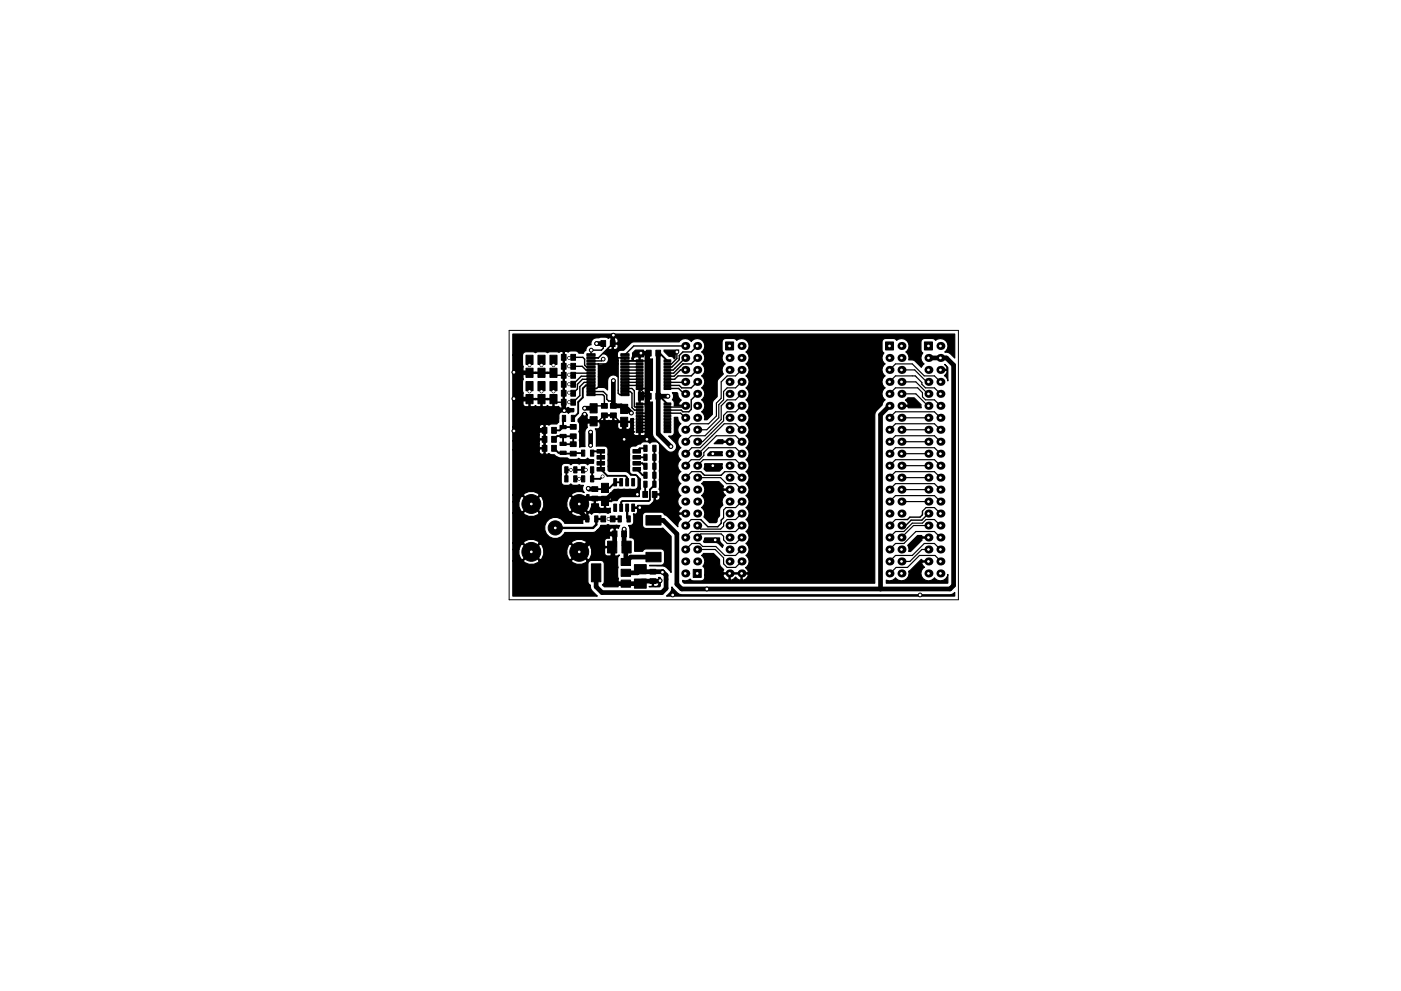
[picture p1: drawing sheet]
<svg xmlns="http://www.w3.org/2000/svg" width="297mm" height="210mm" viewBox="0 0 297 210" stroke-linecap="round" stroke-linejoin="round" font-family="sans-serif">
<path d="M107.9 70.1h95.3v57.1h-95.3z" fill="none" stroke="#000" stroke-width=".21"/>
<g fill="#000" stroke="#000" stroke-width=".21">
<path d="M111.5 75.4h1.5v1.9h-1.5zM111.5 78.1h1.5v2h-1.5zM114.1 75.4h1.5v1.9h-1.5zM114.1 78.1h1.5v2h-1.5zM116.6 75.4h1.5v1.9h-1.5zM116.6 78.1h1.5v2h-1.5zM119 79h1v1.2h-1zM119 77.1h1v1.2h-1zM119 75.2h1v1.2h-1zM121 79h1v1.2h-1zM121 77.1h1v1.2h-1zM121 75.2h1v1.2h-1z"/>
<path d="M124.4 75h1.8v.5h-1.8zM124.4 75.7h1.8v.4h-1.8zM124.4 76.3h1.8v.5h-1.8zM124.4 77h1.8v.4h-1.8zM124.4 77.6h1.8v.5h-1.8zM124.4 78.3h1.8v.4h-1.8zM124.4 78.9h1.8v.5h-1.8zM124.4 79.6h1.8v.4h-1.8zM127.4 72.3h1v1.2h-1zM129.4 72.3h1v1.2h-1zM131.6 79.6h1.8v.4h-1.8zM131.6 78.9h1.8v.5h-1.8z"/>
<path d="M131.6 78.3h1.8v.4h-1.8zM131.6 77.6h1.8v.5h-1.8zM131.6 77h1.8v.4h-1.8zM131.6 76.3h1.8v.5h-1.8zM131.6 75.7h1.8v.4h-1.8zM131.6 75h1.8v.5h-1.8zM134.9 76.3h1.4v.5h-1.4zM134.9 77h1.4v.4h-1.4zM134.9 77.6h1.4v.5h-1.4zM134.9 78.3h1.4v.4h-1.4zM134.9 78.9h1.4v.5h-1.4zM137.1 74.3h1v1.2h-1z"/>
<path d="M139.1 74.3h1v1.2h-1zM140.8 78.9h1.4v.5h-1.4zM140.8 78.3h1.4v.4h-1.4zM140.8 77.6h1.4v.5h-1.4zM140.8 77h1.4v.4h-1.4zM140.8 76.3h1.4v.5h-1.4zM153.8 72.6h1.7v1.7h-1.7zM187.7 72.6h1.7v1.7h-1.7zM196 72.6h1.7v1.7h-1.7zM111.5 81h1.5v1.9h-1.5zM111.5 83.7h1.5v2h-1.5zM114.1 81h1.5v1.9h-1.5z"/>
<path d="M114.1 83.7h1.5v2h-1.5zM115 94.5h1v1.2h-1zM115 92.6h1v1.2h-1zM115 90.7h1v1.2h-1zM116.6 81h1.5v1.9h-1.5zM116.6 83.7h1.5v2h-1.5zM117 94.5h1v1.2h-1zM117 92.6h1v1.2h-1zM117 90.7h1v1.2h-1zM118.7 93.8h1.3v.7h-1.3zM118.7 95.7h1.3v.7h-1.3zM118.7 90.3h1.3v.7h-1.3z"/>
<path d="M118.7 92.2h1.3v.7h-1.3zM119.2 88.1h.7v1.3h-.7zM119 84.7h1v1.3h-1zM119 80.9h1v1.3h-1zM119 82.8h1v1.3h-1zM119.7 99h.7v1.3h-.7zM121.1 88.1h.7v1.3h-.7zM121 84.7h1v1.3h-1zM121 80.9h1v1.3h-1zM121 82.8h1v1.3h-1zM120.9 95.7h1.3v1h-1.3zM120.9 93.7h1.3v1h-1.3z"/>
<path d="M120.9 92.1h1.3v1h-1.3zM120.9 90.1h1.3v1h-1.3zM121.6 99h.7v1.3h-.7zM123.3 95.5h.7v1.3h-.7zM125.1 85.7h1.5v1.9h-1.5zM125.1 88.4h1.5v2h-1.5zM125.2 95.5h.7v1.3h-.7zM124.4 80.2h1.8v.5h-1.8zM124.4 80.9h1.8v.4h-1.8zM124.4 81.5h1.8v.5h-1.8zM124.4 82.2h1.8v.4h-1.8zM124.4 82.8h1.8v.5h-1.8z"/>
<path d="M124.4 83.5h1.8v.4h-1.8zM127.5 85.6h1.3v1h-1.3zM127.5 87.6h1.3v1h-1.3zM126.6 95.4h1.6v.7h-1.6zM126.6 96.6h1.6v.8h-1.6zM126.6 97.9h1.6v.8h-1.6zM126.6 99.2h1.6v.7h-1.6zM129.4 85.6h1.3v1h-1.3zM129.4 87.6h1.3v1h-1.3zM131.6 85.8h1.5v1.9h-1.5zM131.6 88.5h1.5v2h-1.5zM131.6 83.5h1.8v.4h-1.8z"/>
<path d="M131.6 82.8h1.8v.5h-1.8zM131.6 82.2h1.8v.4h-1.8zM131.6 81.5h1.8v.5h-1.8zM131.6 80.9h1.8v.4h-1.8zM131.6 80.2h1.8v.5h-1.8zM134.9 79.6h1.4v.4h-1.4zM134.9 80.2h1.4v.5h-1.4zM134.9 80.9h1.4v.4h-1.4zM134.9 81.5h1.4v.5h-1.4zM134.9 82.2h1.4v.4h-1.4zM134.9 85.5h1.4v.4h-1.4zM134.9 86.1h1.4v.5h-1.4z"/>
<path d="M134.9 86.8h1.4v.4h-1.4zM134.9 87.4h1.4v.5h-1.4zM134.9 88.1h1.4v.4h-1.4zM134.9 88.7h1.4v.5h-1.4zM134.9 89.4h1.4v.4h-1.4zM134.9 90h1.4v.5h-1.4zM134.9 90.7h1.4v.4h-1.4zM134.9 91.3h1.4v.5h-1.4zM134.2 99.2h1.6v.7h-1.6zM134.2 97.9h1.6v.8h-1.6zM134.2 96.6h1.6v.8h-1.6zM134.2 95.4h1.6v.7h-1.6z"/>
<path d="M136.5 98.3h.7v1.3h-.7zM136.5 96.4h.7v1.3h-.7zM136.5 94.5h.7v1.3h-.7zM137.1 83.4h1v1.3h-1zM138.4 98.3h.7v1.3h-.7zM138.4 96.4h.7v1.3h-.7zM138.4 94.5h.7v1.3h-.7zM139.1 83.4h1v1.3h-1zM140.8 82.2h1.4v.4h-1.4zM140.8 81.5h1.4v.5h-1.4zM140.8 80.9h1.4v.4h-1.4zM140.8 80.2h1.4v.5h-1.4z"/>
<path d="M140.8 79.6h1.4v.4h-1.4zM140.8 91.3h1.4v.5h-1.4zM140.8 90.7h1.4v.4h-1.4zM140.8 90h1.4v.5h-1.4zM140.8 89.4h1.4v.4h-1.4zM140.8 88.7h1.4v.5h-1.4zM140.8 88.1h1.4v.4h-1.4zM140.8 87.4h1.4v.5h-1.4zM140.8 86.8h1.4v.4h-1.4zM140.8 86.1h1.4v.5h-1.4zM140.8 85.5h1.4v.4h-1.4zM119.7 100.9h.7v1.3h-.7z"/>
<path d="M121.6 100.9h.7v1.3h-.7zM123.3 99h.7v1.3h-.7zM123.3 100.9h.7v1.3h-.7zM124.2 109.5h.7v1.3h-.7zM125.2 99h.7v1.3h-.7zM125.5 103.3h1.2v1h-1.2zM125.5 105.3h1.2v1h-1.2zM125.2 100.9h.7v1.3h-.7zM126.1 109.5h.7v1.3h-.7zM125.4 119.6h2v3.8h-2zM127.5 102.5h1.5v2h-1.5zM127.5 105.3h1.5v1.9h-1.5z"/>
<path d="M127.4 109.5h1v1.2h-1zM129.4 109.5h1v1.2h-1zM130.1 106.9h.6v1.6h-.6zM130.1 101.5h.6v1.6h-.6zM128.8 114.8h2v2.5h-2zM129.8 112.7h1v1.2h-1zM131 109.5h.7v1.3h-.7zM131.4 106.9h.6v1.6h-.6zM131.4 101.5h.6v1.6h-.6zM131.8 112.7h1v1.2h-1zM132.9 109.5h.7v1.3h-.7zM132.7 106.9h.6v1.6h-.6z"/>
<path d="M132.7 101.5h.6v1.6h-.6zM131.7 118.5h2v1.5h-2zM131.9 114.8h1.9v2.5h-1.9zM134.5 119.8h2.5v1.9h-2.5zM133.9 106.9h.6v1.6h-.6zM133.9 101.5h.6v1.6h-.6zM136.3 104.3h1v1.2h-1zM136.5 102.1h.7v1.3h-.7zM136.5 100.2h.7v1.3h-.7zM138.3 104.3h1v1.2h-1zM138.4 102.1h.7v1.3h-.7zM138.4 100.2h.7v1.3h-.7z"/>
<path d="M137 117.2h3.2v2h-3.2zM137 109.4h3.2v2h-3.2zM131.7 120.8h2v1.5h-2zM131.7 123.1h2v1.5h-2zM134.5 122.8h2.5v2h-2.5zM137.8 120.8h1.3v1h-1.3zM137.8 122.8h1.3v1h-1.3zM147 120.8h1.7v1.7h-1.7z"/>
<circle cx="109" cy="79" r=".4"/>
<circle cx="112.3" cy="77.5" r=".3"/>
<circle cx="114.8" cy="77.5" r=".3"/>
<circle cx="117.3" cy="77.5" r=".3"/>
<circle cx="120.7" cy="79.5" r=".3"/>
<circle cx="120.7" cy="77.7" r=".3"/>
<circle cx="120.7" cy="75.9" r=".3"/>
<circle cx="125.3" cy="74.3" r=".4"/>
<circle cx="126.5" cy="72.9" r=".4"/>
<circle cx="127.9" cy="76.2" r=".4"/>
<circle cx="130" cy="71.1" r=".4"/>
<circle cx="135.9" cy="74.9" r=".4"/>
<circle cx="143.5" cy="74.7" r=".4"/>
<circle cx="109" cy="84.6" r=".4"/>
<circle cx="109" cy="91.4" r=".4"/>
<circle cx="112.3" cy="83.1" r=".3"/>
<circle cx="114.8" cy="83.1" r=".3"/>
<circle cx="117.3" cy="83.1" r=".3"/>
<circle cx="119.6" cy="87.1" r=".4"/>
<circle cx="120.7" cy="85.3" r=".3"/>
<circle cx="120.7" cy="81.5" r=".3"/>
<circle cx="120.7" cy="83.3" r=".3"/>
<circle cx="121" cy="99.7" r=".3"/>
<circle cx="124" cy="86.6" r=".4"/>
<circle cx="124" cy="87.9" r=".4"/>
<circle cx="124.2" cy="99.7" r=".3"/>
<circle cx="125.2" cy="94.5" r=".4"/>
<circle cx="125.2" cy="91.7" r=".4"/>
<circle cx="130" cy="80.8" r=".4"/>
<circle cx="132.3" cy="93.2" r=".4"/>
<circle cx="133.9" cy="87.6" r=".4"/>
<circle cx="137.2" cy="93.2" r=".4"/>
<circle cx="141.6" cy="84.1" r=".4"/>
<circle cx="142.2" cy="94.7" r=".4"/>
<circle cx="151.1" cy="96.3" r=".4"/>
<circle cx="151.1" cy="98.8" r=".4"/>
<circle cx="112.6" cy="106.9" r="2"/>
<circle cx="112.6" cy="117.1" r="2"/>
<circle cx="117.7" cy="112" r="1.5"/>
<circle cx="122.8" cy="106.9" r="2"/>
<circle cx="122.8" cy="117.1" r="2"/>
<circle cx="122.8" cy="101.6" r=".3"/>
<circle cx="124.7" cy="103.6" r=".4"/>
<circle cx="127.8" cy="101.1" r=".3"/>
<circle cx="129" cy="110.1" r=".3"/>
<circle cx="132.3" cy="112.3" r=".4"/>
<circle cx="135.1" cy="104.9" r=".4"/>
<circle cx="135.6" cy="107.7" r=".4"/>
<circle cx="151.6" cy="114.5" r=".4"/>
<circle cx="140" cy="123.2" r=".4"/>
<circle cx="140.5" cy="121.4" r=".4"/>
<circle cx="142.6" cy="126.2" r=".4"/>
<circle cx="149.9" cy="125" r=".4"/>
<circle cx="195.1" cy="126.2" r=".4"/>
</g>
<g fill="#000">
<circle cx="145.3" cy="78.5" r=".85"/>
<circle cx="145.3" cy="75.9" r=".85"/>
<circle cx="145.3" cy="73.4" r=".85"/>
<circle cx="147.8" cy="78.5" r=".85"/>
<circle cx="147.8" cy="73.4" r=".85"/>
<circle cx="147.8" cy="75.9" r=".85"/>
<circle cx="154.7" cy="78.5" r=".85"/>
<circle cx="154.7" cy="75.9" r=".85"/>
<circle cx="157.2" cy="78.5" r=".85"/>
<circle cx="157.2" cy="73.4" r=".85"/>
<circle cx="157.2" cy="75.9" r=".85"/>
<circle cx="188.6" cy="78.5" r=".85"/>
<circle cx="188.6" cy="75.9" r=".85"/>
<circle cx="191.1" cy="78.5" r=".85"/>
<circle cx="191.1" cy="73.4" r=".85"/>
<circle cx="191.1" cy="75.9" r=".85"/>
<circle cx="196.8" cy="78.5" r=".85"/>
<circle cx="196.8" cy="75.9" r=".85"/>
<circle cx="199.4" cy="73.4" r=".85"/>
<circle cx="199.4" cy="78.5" r=".85"/>
<circle cx="199.4" cy="75.9" r=".85"/>
<circle cx="145.3" cy="96.3" r=".85"/>
<circle cx="145.3" cy="88.6" r=".85"/>
<circle cx="145.3" cy="83.6" r=".85"/>
<circle cx="145.3" cy="81" r=".85"/>
<circle cx="145.3" cy="93.7" r=".85"/>
<circle cx="145.3" cy="86.1" r=".85"/>
<circle cx="145.3" cy="98.8" r=".85"/>
<circle cx="145.3" cy="91.2" r=".85"/>
<circle cx="147.8" cy="93.7" r=".85"/>
<circle cx="147.8" cy="88.6" r=".85"/>
<circle cx="147.8" cy="86.1" r=".85"/>
<circle cx="147.8" cy="96.3" r=".85"/>
<circle cx="147.8" cy="91.2" r=".85"/>
<circle cx="147.8" cy="81" r=".85"/>
<circle cx="147.8" cy="98.8" r=".85"/>
<circle cx="147.8" cy="83.6" r=".85"/>
<circle cx="154.7" cy="93.7" r=".85"/>
<circle cx="154.7" cy="96.3" r=".85"/>
<circle cx="154.7" cy="81" r=".85"/>
<circle cx="154.7" cy="86.1" r=".85"/>
<circle cx="154.7" cy="83.6" r=".85"/>
<circle cx="154.7" cy="91.2" r=".85"/>
<circle cx="154.7" cy="98.8" r=".85"/>
<circle cx="154.7" cy="88.6" r=".85"/>
<circle cx="157.2" cy="96.3" r=".85"/>
<circle cx="157.2" cy="93.7" r=".85"/>
<circle cx="157.2" cy="86.1" r=".85"/>
<circle cx="157.2" cy="81" r=".85"/>
<circle cx="157.2" cy="83.6" r=".85"/>
<circle cx="157.2" cy="88.6" r=".85"/>
<circle cx="157.2" cy="91.2" r=".85"/>
<circle cx="157.2" cy="98.8" r=".85"/>
<circle cx="188.6" cy="96.3" r=".85"/>
<circle cx="188.6" cy="88.6" r=".85"/>
<circle cx="188.6" cy="86.1" r=".85"/>
<circle cx="188.6" cy="93.7" r=".85"/>
<circle cx="188.6" cy="83.6" r=".85"/>
<circle cx="188.6" cy="91.2" r=".85"/>
<circle cx="188.6" cy="81" r=".85"/>
<circle cx="188.6" cy="98.8" r=".85"/>
<circle cx="191.1" cy="86.1" r=".85"/>
<circle cx="191.1" cy="83.6" r=".85"/>
<circle cx="191.1" cy="88.6" r=".85"/>
<circle cx="191.1" cy="91.2" r=".85"/>
<circle cx="191.1" cy="93.7" r=".85"/>
<circle cx="191.1" cy="96.3" r=".85"/>
<circle cx="191.1" cy="81" r=".85"/>
<circle cx="191.1" cy="98.8" r=".85"/>
<circle cx="196.8" cy="91.2" r=".85"/>
<circle cx="196.8" cy="86.1" r=".85"/>
<circle cx="196.8" cy="88.6" r=".85"/>
<circle cx="196.8" cy="93.7" r=".85"/>
<circle cx="196.8" cy="81" r=".85"/>
<circle cx="196.8" cy="83.6" r=".85"/>
<circle cx="196.8" cy="96.3" r=".85"/>
<circle cx="196.8" cy="98.8" r=".85"/>
<circle cx="199.4" cy="88.6" r=".85"/>
<circle cx="199.4" cy="83.6" r=".85"/>
<circle cx="199.4" cy="86.1" r=".85"/>
<circle cx="199.4" cy="91.2" r=".85"/>
<circle cx="199.4" cy="93.7" r=".85"/>
<circle cx="199.4" cy="96.3" r=".85"/>
<circle cx="199.4" cy="81" r=".85"/>
<circle cx="199.4" cy="98.8" r=".85"/>
<circle cx="145.3" cy="114" r=".85"/>
<circle cx="145.3" cy="119.1" r=".85"/>
<circle cx="145.3" cy="116.6" r=".85"/>
<circle cx="145.3" cy="109" r=".85"/>
<circle cx="145.3" cy="101.3" r=".85"/>
<circle cx="145.3" cy="111.5" r=".85"/>
<circle cx="145.3" cy="103.9" r=".85"/>
<circle cx="145.3" cy="106.4" r=".85"/>
<circle cx="147.8" cy="109" r=".85"/>
<circle cx="147.8" cy="116.6" r=".85"/>
<circle cx="147.8" cy="103.9" r=".85"/>
<circle cx="147.8" cy="119.1" r=".85"/>
<circle cx="147.8" cy="114" r=".85"/>
<circle cx="147.8" cy="111.5" r=".85"/>
<circle cx="147.8" cy="101.3" r=".85"/>
<circle cx="147.8" cy="106.4" r=".85"/>
<circle cx="154.7" cy="103.9" r=".85"/>
<circle cx="154.7" cy="109" r=".85"/>
<circle cx="154.7" cy="116.6" r=".85"/>
<circle cx="154.7" cy="119.1" r=".85"/>
<circle cx="154.7" cy="111.5" r=".85"/>
<circle cx="154.7" cy="114" r=".85"/>
<circle cx="154.7" cy="101.3" r=".85"/>
<circle cx="154.7" cy="106.4" r=".85"/>
<circle cx="157.2" cy="114" r=".85"/>
<circle cx="157.2" cy="119.1" r=".85"/>
<circle cx="157.2" cy="106.4" r=".85"/>
<circle cx="157.2" cy="111.5" r=".85"/>
<circle cx="157.2" cy="116.6" r=".85"/>
<circle cx="157.2" cy="101.3" r=".85"/>
<circle cx="157.2" cy="109" r=".85"/>
<circle cx="157.2" cy="103.9" r=".85"/>
<circle cx="188.6" cy="109" r=".85"/>
<circle cx="188.6" cy="116.6" r=".85"/>
<circle cx="188.6" cy="101.3" r=".85"/>
<circle cx="188.6" cy="103.9" r=".85"/>
<circle cx="188.6" cy="106.4" r=".85"/>
<circle cx="188.6" cy="111.5" r=".85"/>
<circle cx="188.6" cy="119.1" r=".85"/>
<circle cx="188.6" cy="114" r=".85"/>
<circle cx="191.1" cy="111.5" r=".85"/>
<circle cx="191.1" cy="109" r=".85"/>
<circle cx="191.1" cy="116.6" r=".85"/>
<circle cx="191.1" cy="101.3" r=".85"/>
<circle cx="191.1" cy="103.9" r=".85"/>
<circle cx="191.1" cy="106.4" r=".85"/>
<circle cx="191.1" cy="119.1" r=".85"/>
<circle cx="191.1" cy="114" r=".85"/>
<circle cx="196.8" cy="101.3" r=".85"/>
<circle cx="196.8" cy="109" r=".85"/>
<circle cx="196.8" cy="116.6" r=".85"/>
<circle cx="196.8" cy="103.9" r=".85"/>
<circle cx="196.8" cy="106.4" r=".85"/>
<circle cx="196.8" cy="111.5" r=".85"/>
<circle cx="196.8" cy="119.1" r=".85"/>
<circle cx="196.8" cy="114" r=".85"/>
<circle cx="199.4" cy="116.6" r=".85"/>
<circle cx="199.4" cy="101.3" r=".85"/>
<circle cx="199.4" cy="103.9" r=".85"/>
<circle cx="199.4" cy="106.4" r=".85"/>
<circle cx="199.4" cy="109" r=".85"/>
<circle cx="199.4" cy="114" r=".85"/>
<circle cx="199.4" cy="111.5" r=".85"/>
<circle cx="199.4" cy="119.1" r=".85"/>
<circle cx="145.3" cy="121.7" r=".85"/>
<circle cx="154.7" cy="121.7" r=".85"/>
<circle cx="157.2" cy="121.7" r=".85"/>
<circle cx="188.6" cy="121.7" r=".85"/>
<circle cx="191.1" cy="121.7" r=".85"/>
<circle cx="196.8" cy="121.7" r=".85"/>
<circle cx="199.4" cy="121.7" r=".85"/>
</g>
<g fill="none" stroke="#000" stroke-width="1">
<path d="M109 79l3.3 .1M126.5 72.9h1.4M130 71.1l-.1 .2v1.6M135.9 74.9h1.7l-.4 .4v8.4l.4 .4-.4 .4v8.7M139.6 74.9v17.2l2.6 2.6M196.8 75.9h3.9l1.5 1.6v46.7l-.8 .8h-56.9l-1-1.1v-10.6l-2.9-2.9h-2M109 84.6l3.3 .1M115.5 91.3h-6.4l-.1 .1M119.5 85.3l.1 1.8M124 87.9v1l.4 .5h1.5M124 86.6h1.8M125.2 91.7v2.8"/>
<path d="M125.8 86.6h.1M130 80.8v5.3h1.7l.6 .7h.7l.9 .8M132.3 89.5v3.7M139.6 84.1h2M188.6 86.1l-1.9 1.9v37M122.8 117.1l3.9-3.8h3.6v2.4l-.4 .4v6.9l.9 .8h4.8l.5-.5h3.7l.2-.1M124.7 103.6l.2 .2h1.2M132.3 112.3v3.4l.4 .4v3.1l1-1h4.9M135.1 104.9h-5.5l-1.3 1.4-.5-.5h-3.8l-1.2 1.1v1.5l1.7 1.7M135.6 107.7h.1M140.5 121.3v.1M140.5 121.3h-4.4l-.3-.4-.6 .6h-2.5"/>
<path d="M140.5 121.3l.7 .7v2.8l-.9 .9h-12.7l-1.2-1.2v-3"/>
</g>
<g fill="none" stroke="#000" stroke-width=".3">
<path d="M112.3 79.1h5l.6 .5h1.6M112.3 76.3v1.2M114.8 76.3v1.2M117.3 76.3v1.2M119.5 75.8v9.5h-1.5l-.7-.6h-5M120.6 77.7h2.8l.8 .8h1.1M121.4 75.7l.1 .1M121.5 75.8l-.1 .1h-.8M121.5 75.8h2.1l.4 .4v1.3l.4 .4h.9M125.3 75.9h1.6M125.3 79.2h-3.3l-.5 .4h-.7l-.2-.1M125.3 79.8h-2.1l-1.7 1.7h-.9"/>
<path d="M126.9 75.9h.1M126.9 77.2v4.8l-.4 .4M126.9 75.9l3-3v2.4l1.2 1.1v7l.3 .3h1.1M127.9 76.2l-.4 .4h-2.2M127.9 72.9v1l-.4 .4h-2.2v1h.2M130.5 75.9h2v.7M131.1 77.2h-5.8M132.5 77.2h3.1M132.5 79.8h3.1M132.5 77.9h3.1M132.5 78.5h3.1M132.5 79.2h3.1"/>
<path d="M135.6 76.6h1.3l.3 .2v5.4l-.3 .2h-1.3l1.7 1.7h.3M141.2 76.6h.3M143.5 74.7v1.4l-1.1 1.1h-.9M143.6 78.4h.1M144.9 75.9h.4l-2.6 2.6h-1.2M145.3 78.5h-1l-1.4 1.3h-1.4M145.3 73.4h-10.9l-1.9 1.9M147.8 75.9l-1.2 1.3h-1.8l-2 2h-1.3M147.8 73.4l-1.2 1.3h-1.8l-.8 .7v.9l-1.5 1.6h-1M147.8 78.5l-1.2 1.3h-2.8l-.8 .7h-1.5M112.3 81.9v1.2M114.8 81.9v1.2"/>
<path d="M117.3 81.9v1.2M120.6 83.3l.2 .1h.7M121.4 83.3l.1 .1M125.3 83.7h2.5l.3 .4v2h-1.7l-.5 .5M125.3 81.1h-1.4l-1 .9v1.9l-1.4 1.4h-.9M125.3 82.4h1.2M125.3 83.1h2.6l.8 .7v.9l.3 .4h.5l.5 .5v.5M125.3 80.5h-1.8l-1.1 1v1l-.9 .9M125.9 89.4h1l1.2-1.3h1.9l1.4 1.4h.9M126.5 82.4h.1M131.7 86.1l.6 .7M132.5 82.4h1.5l.5 .5v3.3l.1 .2h1"/>
<path d="M132.5 83.1h1.1l.4 .3v3.1l.5 .5h1.1M132.5 81.8h3.1M132.5 81.1h3.1M132.5 80.5h3.1M135.6 85.7h1.2l.4 .4v5.2l-.3 .3h-1.3M135.6 90.9h1.6M135.6 90.3h1.6M135.6 89.6l1.5 .1M135.6 89h1.6M135.6 88.3h1.6M135.6 87.7h1.6M141.5 82.4h2.4l1.1 1.2h.3"/>
<path d="M141.5 87.7h2.8l1 .9M145.3 86.1l-.3 .3h-3.5M145.3 81l-3.8 .1M147.8 83.6l-1.2 1.2v2.1l-.6 .5h-1.2l-.4-.4h-2.9M147.8 81l-1.2 1.3h-2.1l-.5-.5h-2.5M148.6 100.1l.8 .7h3.5l.8-.7M148.6 110.2v.1M153.4 109.8l-.5 .6v.6l-.7 .8h-2.1l-1.5-1.5M195.6 108.5v.7l-.5 .5h-2.2l-.5 .5h-.8M196.8 109l-1.3 1.4h-2.3l-1.2 1.1h-.9"/>
</g>
<g fill="none" stroke="#000" stroke-width=".4">
<path d="M132.5 76.6h3.1M139.6 74.9h.3l1.6 1.7M115.5 91.3v3.8M117.5 95.1l.9 1h1l.2 .1 4-.1M119.4 92.5l2.1 .1v1.6h-2zM119.4 92.5h-1.2l-.7 .7M119.4 90.6l-.7 .7h-1.2M119.6 88.8l-.2 .2v1.6M121 99.7h-.9v1.9M121.5 90.6h-2.1M122 99.7h2.2M125.3 81.8h-1.1l-.6 .6v1.9l-1 1v2.4l-1.1 1.1"/>
<path d="M125.5 99.7v1.9h1.8l.5-.5M125.5 96.1l.4-.3h1.5v3.8l1.4 1.4h3.8l.4 .3v1M135 99.6l1.3 1.2h.5M135 98.3h1.2l.6 .6M135 97h1.8M136.8 95.1h-1.2l-.6 .7M138.7 95.1v7.8l-.9 1v2.1l-.3 .3h-5.5l-.3 .2v1.2M139.6 84.1h.3l1.6 1.6M122 101.6h1.6M127.8 105.8l.5 .5M129 110.1h.9M131.7 102.3h-1.3l-1.2 1.2h-.9l-.3 .3h-1.9"/>
<path d="M136.8 102.7v2.2M138.8 104.9v1.4l-1.4 1.4h-3.2"/>
</g>
<g fill="none" stroke="#000" stroke-width=".25">
<path d="M157.2 78.5l-1.2 1.3h-1.8l-1.3 1.2v3.5l-1 1v2.8l-1.7 1.6h-3.6l-1.3 1.3M188.6 78.5l1.3-1.3h3.5l2.6 2.6h2.1l1.3 1.2M191.1 78.5h2.8l2.6 2.5h.3M147.8 98.8l1.3-1.3h6.9l1.2 1.3M157.2 91.2l-1.2-1.3h-2.5l-5 5.1h-1.8l-1.4 1.3M157.2 93.7l-1.2-1.2h-4.1l-3.8 3.8h-.3M157.2 96.3l-1.2-1.3h-5.8l-1 1v.6l-.9 .9h-1.7l-1.3 1.3M157.2 86.1l-1.2 1.3h-1.8l-.8 .7v1.2l-4.4 4.4h-1.2M157.2 81l-1.2 1.3h-1.8l-.8 .8v1.7l-1 1v2.8l-2.5 2.6h-2.1M157.2 83.6l-1.2 1.2h-1.8l-1.3 1.3v2.9l-3.4 3.5h-2.9l-1.3 1.2M188.6 98.8l1.3-1.3h8.2l1.3 1.3M188.6 96.3l1.3-1.3h8.2l1.3 1.3"/>
<path d="M188.6 93.7l1.3-1.2h8.2l1.3 1.2M188.6 91.2l1.3-1.3h8.2l1.3 1.3M188.6 88.6l1.3-1.2h8.2l1.3 1.2M188.6 83.6l1.3-1.3h4.7l1 1v.9l.6 .6h1.9l1.3 1.3M188.6 81l1.3-1.2h4.2l1.4 1.3v.4l.7 .8h1.9l1.3 1.3M191.1 98.8h5.7M191.1 96.3h5.7M191.1 93.7h5.7M191.1 91.2h5.7M191.1 88.6h5.7M191.1 83.6h3.1l2.6 2.5M191.1 81h3.1l2.6 2.6"/>
<path d="M145.3 116.6l1.4-1.3h1.6l.7 .6h2.8l1.9 2h2.3l1.2-1.3M147.8 116.6h3.8l1.8 1.8v1.2l.8 .8h1.8l1.2-1.3M147.8 114l.8-.7h4.3l.5 .5v.7l.8 .8h1.8l1.2-1.3M147.8 101.3h5l1.3 1.3h1.9l1.2 1.3M148.6 110.2h-2l-1.3 1.3M148.6 100.1h-1.9l-1.4 1.2M153.7 100.1h2.3l1.2 1.2M157.2 109l-1.2 1.2h-1.8l-.8 .8v.6l-.6 .7h-4.2l-.8-.8h.4M157.2 111.5l-1.2 1.3h-9.4l-1.3 1.2M157.2 106.4l-1.2 1.3h-2.1l-.5 .5v1.6M188.6 106.4l1.3-1.2h8.2l1.3 1.2M188.6 103.9l1.3-1.3h8.2l1.3 1.3"/>
<path d="M188.6 101.3l1.3-1.2h8.2l1.3 1.2M191.1 106.4h5.7M191.1 103.9h5.7M191.1 101.3h5.7M191.6 110.2h-1.7l-1.3 1.3M195.6 108.5l.7-.8h1.8l1.3 1.3M196.8 116.6h-1.3l-2.6 2.5h-1.8M196.8 111.5h-3.1l-2.6 2.5M199.4 119.1l-1.2-1.2h-3.3l-2.5 2.5h-2.4l-1.4 1.3M199.4 116.6l-1.3-1.3h-2.1l-2.6 2.6h-3.5l-1.3 1.2h.1M199.4 114l-1.3-1.2h-3.9l-2.6 2.5h-1.7l-1.3 1.3M199.4 111.5l-1.3-1.3h-1.8l-.7 .8h-2.2l-1.8 1.8h-1.7l-1.3 1.2"/>
</g>
<path d="M127.9 110.1h-1.5v1.2l-.7 .7h-8M129.9 110.1h1.5M133 107.7v2.1l.3 .3" fill="none" stroke="#000" stroke-width=".5"/>
<g fill="#000" stroke="#000" stroke-width=".25">
<path d="M140.8 74.3h3.1a1.54 1.54 0 0 0-.8 1.7l-.2 .2a.82 .82 0 0 0-1-.6l-1.1-1zM200.3 77.3l.7 .7v2.8l-.1-.4-.7-.7 .5-.5 .1-.4-.1-.2h-1.5l.1-.3 1.4 .1 .1-.3zM108.7 70.9h93.7v5.1a2.81 2.81 0 0 0-1.7-1.3h-.4a1.57 1.57 0 0 0 .3-2.3 1.57 1.57 0 0 0-2.3-.2l-.6-.4h-1.7a.74 .74 0 0 0-.7 .8v1.7l.4 .6a1.51 1.51 0 0 0 .2 2.3l-.5 .7-1.7-1.5h-1l-.1-1.1-.6-.6 .3-.2a1.59 1.59 0 0 0 0-2.2 1.59 1.59 0 0 0-2.2-.1l-.7-.4h-1.7a.74 .74 0 0 0-.7 .8v1.7l.4 .6a1.51 1.51 0 0 0 .3 2.3 1.51 1.51 0 0 0 0 2.6 1.51 1.51 0 0 0 0 2.5 1.51 1.51 0 0 0 0 2.5l-.6 .7-.1 .4-1.2 1.2-.3 .9v35.7h-40.5l-.3-.3v-.3a1.56 1.56 0 0 0 1.6-.3l.7 .5h1.7a.87 .87 0 0 0 .7-1.3h3.8l.6 .9 .5 .2 .3-.1v-1.2h.2v1.2l.2 .1 .6-.2 .4-.5 .3 .5 .6 .2 .2-.1v-1.2h.3v1.2l.2 .1a1.08 1.08 0 0 0 .9-1.3h-5.1l-.2 .2h-3.8v-1.5l-.4-.3 .3-.5a1.5 1.5 0 0 0-.6-1.8l.4-.5h2.2l1.3 1.3a1.85 1.85 0 0 0 .8 2.2l-.2 .4 .2 .2h5.1l.2-.2-.2-.4-.4-.5a1.51 1.51 0 0 0 0-2.5 1.51 1.51 0 0 0 0-2.6 1.51 1.51 0 0 0 0-2.5 1.51 1.51 0 0 0 0-2.6 1.51 1.51 0 0 0 0-2.5 1.51 1.51 0 0 0 0-2.5 1.51 1.51 0 0 0 0-2.6 1.51 1.51 0 0 0 0-2.5 1.51 1.51 0 0 0 0-2.6 1.51 1.51 0 0 0 0-2.5 1.51 1.51 0 0 0 0-2.5 1.51 1.51 0 0 0 0-2.6 1.51 1.51 0 0 0 0-2.5 1.51 1.51 0 0 0 0-2.6 1.51 1.51 0 0 0 0-2.5 1.51 1.51 0 0 0 0-2.5 1.51 1.51 0 0 0 0-2.6 1.51 1.51 0 0 0 0-2.5 1.57 1.57 0 0 0 .4-2.3 1.57 1.57 0 0 0-2.3-.2l-.7-.4h-1.7a.74 .74 0 0 0-.7 .8v1.7l.4 .6a1.51 1.51 0 0 0 .3 2.3 1.47 1.47 0 0 0-.4 2.1l-1.3 1.4v3.5l-1 1-.1 2.7-1.1 1.2h-.5a1.44 1.44 0 0 0-.7-1.7 1.51 1.51 0 0 0 0-2.6 1.51 1.51 0 0 0 0-2.5 1.51 1.51 0 0 0 0-2.5 1.51 1.51 0 0 0 0-2.6 1.51 1.51 0 0 0 0-2.5 1.57 1.57 0 0 0 .3-2.4 1.57 1.57 0 0 0-2.4 .2 1.57 1.57 0 0 0-2.6 0h-9.6l-.6 .3-1.6 1.5a1.04 1.04 0 0 0-1.3 .5v.7l.2 1-.2 .5v2.9a1.22 1.22 0 0 0-1.3-.3 1.22 1.22 0 0 0-.8 1.2v1.9l-.6-.4-1.3-.1v-4.8h.9a1.16 1.16 0 0 0 1.2-1.2 1.16 1.16 0 0 0-1.1-1.1l1.1-1.1a.55 .55 0 0 0 .8 0v-1h.2v1l.2 .2a.68 .68 0 0 0 .8-.6v-.4l-.1-.2h-1.1v-1.2h.2v1h.9l.1-.2-.1-.7a.59 .59 0 0 0-.9-.1l-.4-.2-.7 .2a4.4 4.4 0 0 0-3.3 .2l-.2 .4-.1 .8h-.2a1.25 1.25 0 0 0-.9 1.2l-.5 .6-1-.1-.4-.4a2.17 2.17 0 0 0-1.8 .2l-.7-.1-.1 .1v11.7a.55 .55 0 0 0 .8 0l.2 .2 1 .1-.1 .7a.92 .92 0 0 0-1.1 .3 1.21 1.21 0 0 0-2 .4v1.5l-.4 .4-1.1-.1-.6 .3a.55 .55 0 0 0-.8 0v6l.1 .2 .7-.2 .3 .2 .8 .1 .9 .6 2 .2a2.45 2.45 0 0 0 2 .1l.3-.2 .3 .3a1.51 1.51 0 0 0 1.6-.3l.3 .3h1v.2l-.1 .6h-.9l-.3 .3-.1-.1a1.62 1.62 0 0 0-1.7 0l-.5-.2h-.7l-.6 .3a1.21 1.21 0 0 0-2 .4v1.7a2.57 2.57 0 0 0 .2 2.1 1.45 1.45 0 0 0 1.8-.1l.3 .2a1.77 1.77 0 0 0 1.5-.1l.9 .2-.1 .2a1.23 1.23 0 0 0 .3 1.3 2.14 2.14 0 0 0-2.8 .6l1.7 1.6 1.7-1.6-.1-.2 .5 .1v.3l-.2-.1-1.7 1.7 1.7 1.7 .4-.2 .3-1v-.5h.4l.2-.2v-1.1h.3l-.1 1.1 .2 .2h.5l.1 .7 .4 .3h.6l.1-.2v-1.6h1.4l.2-.1-.1-1 .2-.7 .4-.5h3.7a1.04 1.04 0 0 0 1.3-.4l.1-1.9a.74 .74 0 0 0-.8-.7h-.8l-.5-.5-.6-.3h-3.4l-.3-.2v-3.4a1.46 1.46 0 0 0-.4-1.7h-2.1v-3l-.2-.7h.5l.4-.3 .1-.9h3.7v.8l.6 .5h.5l.2-.1v-1.4h.3v1.4l.1 .1 .8-.1 .3-.4v-.8l-.1-.2-6.4 .2-.1-.3h-2.5l-.1 .2 .1 1-.5 .5-.1 .5v3.1l-1.1 .1-.1-1.6a2.18 2.18 0 0 0-.1-1.7 2.02 2.02 0 0 0 0-2.1h-.1v-.5l.6-.7 .3-.6 .9 .1 .2 .3-.1 1 .1 .2h3.3l.1-.2v-.9h.3v.9l.1 .2h1.4l.1-.2v-.9h-1.9v-.2h2.2v1.1l.1 .2 3.3 .1 .1-.2v-.4h.6l.1 .2-.2 .3 .2 .3-.2 .3a.52 .52 0 0 1 0 .7l.1 .3a.6 .6 0 0 0 .2 .8l-.3 .2 .3 .4 .8 .1 .2-.1v-4.1h.2v4.1l.2 .1 .8-.1 .3-.4-.3-.2 .3-.4a.52 .52 0 0 1 0-.8l-.2-.2 .2-.3a.52 .52 0 0 1 0-.8l-.2-.2 .2-.3a.52 .52 0 0 1 0-.8l-.1-.2a2.87 2.87 0 0 0-.1-2.1l.2-.3 .4-.1v-1h-.8l-.2 .2v.5h-.5l-.2 .1v.4h-.2l-.1-2.2 .1-.5h.2v.4l.2 .2h.5v.5l.2 .1h.8v-.9l-.4-.2-.2-.3 .3-.5v-5l-.3-.6 .2-.2 .4-.2v-.9h-.8l-.2 .1v.5h-.5l-.2 .2v.4h-.2v-.4l-.2-.2h-.5l-.5 .3v.3h-.3l.1-1.4 .6-.6h1.7l.2 .5h1.1v1.2l.1 .2 .5-.1v6.8l-.5-.1-.1 .2v2.2l.1 .1h.5v6.8l.4 .8 3.1 3a1.23 1.23 0 0 0 1.5-.5 1.23 1.23 0 0 0-.2-1.5l-1.3-1.4h.4a.99 .99 0 0 0 .8-1.4v-2.6h.7l.1 .7 .6 .7-.3 .2a1.54 1.54 0 0 0 .3 2.4 1.51 1.51 0 0 0 0 2.5 1.51 1.51 0 0 0 0 2.5 1.51 1.51 0 0 0 0 2.6 1.51 1.51 0 0 0 0 2.5 1.51 1.51 0 0 0 0 2.6 1.51 1.51 0 0 0 .1 2.5l-.5 .5-.2 .4 .2 .2h1.4v.3h-1.4l-.2 .2 .2 .4 .5 .5-.7 .7-.1 .9-2.2-2.3-.6-.3-.5-.5h-3.4a.74 .74 0 0 0-.8 .7v2l.2 .5 .6 .2 3.5-.1 1.8 1.8v7.7l-1.4-1.3-3.1-.1v-.2h2.4l.5-.2 .2-.5v-2a.74 .74 0 0 0-.7-.7h-3.2l-.6 .2-.1 .3h-1.7l-.1-2.4a.84 .84 0 0 0-1-.5l.1-1.8-.3-.8h.3a.74 .74 0 0 0 .8-.7l-.1-1.7 .1-.1 .3 .1 .4-.2 .1-.9-.2-.1h-.9v-.3h.9l.2-.4 2.7-.1 .8-.7v-1.4h.2v1l.2 .2a.68 .68 0 0 0 .8-.6v-.4l-.1-.2h-1.1v-.3l1.1 .1 .1-.2v-.5l-.2-.3 .1-.4v-8.9l-.2-.5-.2-.2a1.51 1.51 0 0 0-1.6 .3l-.3-.3a1.43 1.43 0 0 0-1.7 .4l-.5 .1-.5 .3h-.6a.74 .74 0 0 0-.7 .8v3.5a1.46 1.46 0 0 0 .4 1.7l.9 .1 1 .9v2.1l-.2 .6v1.1h-3.6l-.7 .2-.5 .6-.9 .1-.3 .2-1.2-.1v1.3l.2 .2 .8-.1v.9l-.5 .2-.5-.2h-2.3l-.7 .4-.6-.3-.1 .2v1.2h-1l-.2 .2 .1 .6h-3.9l-.1-.3a2.26 2.26 0 0 0-3.4-.4 2.26 2.26 0 0 0 .2 3.5 2.26 2.26 0 0 0 3.3-.8h6l.4-.1 .5-.4h2.6v.5l.1 .2h.9v-1l-.2-.2a.68 .68 0 0 0-.8 .5h-2.6l.5-.5 .3-.5h1a.72 .72 0 0 1 1 0h2l-.3 .6-.5-.1-.2 .2v1.2h-1.1l-.1 .2v.6l-.7 .1-.3 .4v1.1l.1 .1h1.6v1.9l.2 .2h.8l.4-.3v.1l-.4 .7 .2 5 .1 .2h4.7v.2l-4.7 .1-.1 .1v.4h-3l-.4-.4 .4-.7v-4l-.4-.4-.3-.1h-2a.74 .74 0 0 0-.8 .7l.1 4.1 .5 .4 .1 .8 .2 .4 1.1 1.2h-17.9v-7.5h2.3l.2 .3a2.29 2.29 0 0 0 3.1-.3h6.8l.2 .3a2.29 2.29 0 0 0 3.2-.3l-1.7-1.7-1.7 1.7h-6.8l-1.7-1.7-1.6 1.7h-2.3v-2.4h1.3v1l.4 1 .4 .2 1.7-1.7h.3l1.7 1.7 .4-.2 .4-1v-1h4.9v1l.4 1 .3 .2 1.7-1.7h.4l1.7 1.7a2.11 2.11 0 0 0 .7-2.4h2.8v1l.3 .5 1 .1 .2-.2v-1.6l-4.3 .2-.3-.8-.4-.2-1.7 1.7h-.4l-1.7-1.7-.3 .2-.4 1h-4.9l-.4-1-.4-.2-1.7 1.7h-.3l-1.7-1.7-.4 .2-.4 1h-1.3v-1.4h2.3l1.6 1.7 1.7-1.7h6.8l1.7 1.7 1.7-1.7-.2-.4a2.29 2.29 0 0 0-3.2 .4h-6.8l-.2-.4a2.29 2.29 0 0 0-3.1 .4h-2.3v-6.4h2.3l.2 .4a2.29 2.29 0 0 0 3.1-.4h6.8l.2 .4 1 .4 1.2-.1 .2 .5h.7l.1-1.2-1.7-1.7-1.7 1.7h-6.8l-1.7-1.7-1.6 1.7h-2.3v-2.4h1.3v1.1l.4 .9 .4 .2 1.7-1.7h.3l1.7 1.7 .4-.2 .4-1v-1h4.9v1.1l.4 .9 .3 .2 1.7-1.7-1.7-1.7-.3 .3-.4 .9h-4.9l-.4-.9-.4-.3-1.7 1.7h-.3l-1.7-1.7-.4 .3-.4 .9h-1.3v-1.3h2.3l1.6 1.6 1.7-1.6-.2-.4a2.29 2.29 0 0 0-3.1 .4h-2.3v-9.7h5.6v.5a.61 .61 0 0 0 1 .3v-1h-.8l-.2 .2h-5.6v-1.9h5.6v1.3l.2 .2h.8v-1.7h-.8l-.2 .2h-5.6v-1.9h5.6v1.3l.2 .2h.8v-1.7h-.8l-.2 .2h-5.6v-1h5.6v.4l.2 .2h.8v-1a.6 .6 0 0 0-1 .4h-5.6v-5.6h2.2l.1 1 .4 .3h.6l.1-.2v-1.3h.3v1.3l.2 .2h.5l.4-.3 .4 .3h.6l.2-.2v-1.3h.2v1.3l.2 .2h.6l.4-.3 .4 .3h.6l.1-.2v-1.3h-6.2l-.1 .2h-2.2v-9.6h2.1v1.9l.2 .5-.1 1 .1 .2h6.5v.2h-6.5l-.1 .2 .1 1-.2 .6v1.9l.2 .5-.1 1 .1 .2 6.5-.1v1.6l.1 .2 .8-.1 .1 .1a.59 .59 0 0 0 .9 .1v-11.7l-.2-.1-.7 .2-.4-.2h-1.5l-.5 .2-.5-.2h-1.5l-.6 .2-.5-.2h-1.5a.74 .74 0 0 0-.7 .8h-2.1zM142.5 83.3h1l.2 .2a1.44 1.44 0 0 0 .8 1.4l-.5 .4-.2 .4 .2 .3h1.4v.2l-2.5-.1 .1-.2a.94 .94 0 0 0-.5-1.1 1.15 1.15 0 0 0 0-1.5zM149.5 98.4h3.7v1l-.7 .6h-2.8l-.4-.5zM150.1 96.4l.5-.6h2.6v.9h-3.1zM152.2 93.3h1.1l.1 .3h1.4v.2h-1.4l-.1 .3h-1.9zM154.6 91l.2 .1v.2h-.3zM154.5 88.5h.3v.3h-.2zM192 84.9l.5-.5h1.3l1.5 1.5v.6h-2.7l-.1-.3h-1.5v-.2h1.5l.1-.3-.2-.4zM149.4 114.1h3.2a1.48 1.48 0 0 0 .8 1.6l-.2 .4-1.1-.9-2.8-.1-.2-.2zM149.1 102.2h3.3l1 1-.2 .3 .2 .3h1.4v.2h-1.4l-.2 .2 .2 .4 .5 .5a1.49 1.49 0 0 0-.6 2l-.7 .8v1.6a1.18 1.18 0 0 0-.6 1.2l-.2 .2h-1.4l-1.2-1.2a1.48 1.48 0 0 0-.5-2 1.51 1.51 0 0 0 0-2.5 1.51 1.51 0 0 0 0-2.6z"/>
<path d="M154.5 108.8h.3v.3h-.2zM191 108.8h.3v.3h-.3zM187.9 123.1h.1a1.61 1.61 0 0 0 1.9-.5 1.58 1.58 0 0 0 1.9 .5 1.58 1.58 0 0 0 .9-1.9l2.6-2.5h.1l.1 .3h1.5v.3l-1.5-.1-.1 .3 .2 .4 .4 .4a1.57 1.57 0 0 0-.3 2.5 1.57 1.57 0 0 0 2.4-.2 1.58 1.58 0 0 0 1.7 .6 1.58 1.58 0 0 0 1.2-1.3l-.1 1.8h-13zM194.5 113.6h.9l.1 .3h1.5v.3h-1.5v.4l-2.4 2.4h-.4v-.4l-.3-.9zM138.3 123.2h1.2l.2-.2-.1-.5h.4v1.8l-.2 .2h-2.2l.7-.2v-.9h.3v.9l.1 .1h.5a.61 .61 0 0 0 .3-1h-1.2zM142.5 124.5l.1 .2a3.1 3.1 0 0 0 1.9 1.5h56.9l.5-.1 .5-.4v.8h-61.1a2.34 2.34 0 0 0 1.2-2z"/>
</g>
<g fill="#fff" stroke="#fff" stroke-width=".21">
<circle cx="142.6" cy="126.2" r=".17"/>
<circle cx="195.1" cy="126.2" r=".17"/>
<circle cx="151.6" cy="114.5" r=".17"/>
<circle cx="151.1" cy="98.8" r=".17"/>
<circle cx="151.1" cy="96.3" r=".17"/>
<circle cx="124" cy="87.9" r=".17"/>
<circle cx="143.5" cy="74.7" r=".17"/>
<circle cx="119.6" cy="87.1" r=".17"/>
<circle cx="137.2" cy="93.2" r=".17"/>
<circle cx="132.3" cy="93.2" r=".17"/>
<circle cx="135.6" cy="107.7" r=".17"/>
<circle cx="135.1" cy="104.9" r=".17"/>
<circle cx="140" cy="123.2" r=".17"/>
<circle cx="109" cy="91.4" r=".17"/>
<circle cx="135.9" cy="74.9" r=".17"/>
<circle cx="130" cy="71.1" r=".17"/>
<circle cx="109" cy="79" r=".17"/>
<circle cx="109" cy="84.6" r=".17"/>
<circle cx="125.2" cy="94.5" r=".17"/>
<circle cx="125.2" cy="91.7" r=".17"/>
<circle cx="125.3" cy="74.3" r=".17"/>
<circle cx="127.9" cy="76.2" r=".17"/>
<circle cx="126.5" cy="72.9" r=".17"/>
<circle cx="130" cy="80.8" r=".17"/>
<circle cx="133.9" cy="87.6" r=".17"/>
<circle cx="124.7" cy="103.6" r=".17"/>
<circle cx="132.3" cy="112.3" r=".17"/>
<circle cx="124" cy="86.6" r=".17"/>
<circle cx="141.6" cy="84.1" r=".17"/>
<circle cx="140.5" cy="121.4" r=".17"/>
<circle cx="142.2" cy="94.7" r=".17"/>
<circle cx="122.8" cy="101.6" r=".17"/>
<circle cx="120.6" cy="81.5" r=".17"/>
<circle cx="117.3" cy="83.1" r=".17"/>
<circle cx="124.2" cy="99.7" r=".17"/>
<circle cx="120.6" cy="75.9" r=".17"/>
<circle cx="117.3" cy="77.5" r=".17"/>
<circle cx="149.9" cy="125" r=".17"/>
<circle cx="120.6" cy="79.5" r=".17"/>
<circle cx="112.3" cy="77.5" r=".17"/>
<circle cx="120.6" cy="77.7" r=".17"/>
<circle cx="114.8" cy="77.5" r=".17"/>
<circle cx="121" cy="99.7" r=".17"/>
<circle cx="112.3" cy="83.1" r=".17"/>
<circle cx="120.6" cy="85.3" r=".17"/>
<circle cx="120.6" cy="83.3" r=".17"/>
<circle cx="114.8" cy="83.1" r=".17"/>
<circle cx="129" cy="110.1" r=".17"/>
<circle cx="127.8" cy="101.1" r=".17"/>
<circle cx="147.8" cy="121.7" r=".17"/>
<circle cx="145.3" cy="121.7" r=".17"/>
<circle cx="147.8" cy="119.1" r=".17"/>
<circle cx="145.3" cy="119.1" r=".17"/>
<circle cx="147.8" cy="116.6" r=".17"/>
<circle cx="145.3" cy="116.6" r=".17"/>
<circle cx="147.8" cy="114" r=".17"/>
<circle cx="145.3" cy="114" r=".17"/>
<circle cx="147.8" cy="111.5" r=".17"/>
<circle cx="145.3" cy="111.5" r=".17"/>
<circle cx="147.8" cy="109" r=".17"/>
<circle cx="145.3" cy="109" r=".17"/>
<circle cx="147.8" cy="106.4" r=".17"/>
<circle cx="145.3" cy="106.4" r=".17"/>
<circle cx="147.8" cy="103.9" r=".17"/>
<circle cx="145.3" cy="103.9" r=".17"/>
<circle cx="147.8" cy="101.3" r=".17"/>
<circle cx="145.3" cy="101.3" r=".17"/>
<circle cx="147.8" cy="98.8" r=".17"/>
<circle cx="145.3" cy="98.8" r=".17"/>
<circle cx="147.8" cy="96.3" r=".17"/>
<circle cx="145.3" cy="96.3" r=".17"/>
<circle cx="147.8" cy="93.7" r=".17"/>
<circle cx="145.3" cy="93.7" r=".17"/>
<circle cx="147.8" cy="91.2" r=".17"/>
<circle cx="145.3" cy="91.2" r=".17"/>
<circle cx="147.8" cy="88.6" r=".17"/>
<circle cx="145.3" cy="88.6" r=".17"/>
<circle cx="147.8" cy="86.1" r=".17"/>
<circle cx="145.3" cy="86.1" r=".17"/>
<circle cx="147.8" cy="83.6" r=".17"/>
<circle cx="145.3" cy="83.6" r=".17"/>
<circle cx="147.8" cy="81" r=".17"/>
<circle cx="145.3" cy="81" r=".17"/>
<circle cx="147.8" cy="78.5" r=".17"/>
<circle cx="145.3" cy="78.5" r=".17"/>
<circle cx="147.8" cy="75.9" r=".17"/>
<circle cx="145.3" cy="75.9" r=".17"/>
<circle cx="147.8" cy="73.4" r=".17"/>
<circle cx="145.3" cy="73.4" r=".17"/>
<circle cx="117.7" cy="112" r=".17"/>
<circle cx="122.8" cy="117.1" r=".17"/>
<circle cx="112.6" cy="117.1" r=".17"/>
<circle cx="112.6" cy="106.9" r=".17"/>
<circle cx="122.8" cy="106.9" r=".17"/>
<circle cx="196.8" cy="73.4" r=".17"/>
<circle cx="199.4" cy="73.4" r=".17"/>
<circle cx="196.8" cy="75.9" r=".17"/>
<circle cx="199.4" cy="75.9" r=".17"/>
<circle cx="196.8" cy="78.5" r=".17"/>
<circle cx="199.4" cy="78.5" r=".17"/>
<circle cx="196.8" cy="81" r=".17"/>
<circle cx="199.4" cy="81" r=".17"/>
<circle cx="196.8" cy="83.6" r=".17"/>
<circle cx="199.4" cy="83.6" r=".17"/>
<circle cx="196.8" cy="86.1" r=".17"/>
<circle cx="199.4" cy="86.1" r=".17"/>
<circle cx="196.8" cy="88.6" r=".17"/>
<circle cx="199.4" cy="88.6" r=".17"/>
<circle cx="196.8" cy="91.2" r=".17"/>
<circle cx="199.4" cy="91.2" r=".17"/>
<circle cx="196.8" cy="93.7" r=".17"/>
<circle cx="199.4" cy="93.7" r=".17"/>
<circle cx="196.8" cy="96.3" r=".17"/>
<circle cx="199.4" cy="96.3" r=".17"/>
<circle cx="196.8" cy="98.8" r=".17"/>
<circle cx="199.4" cy="98.8" r=".17"/>
<circle cx="196.8" cy="101.3" r=".17"/>
<circle cx="199.4" cy="101.3" r=".17"/>
<circle cx="196.8" cy="103.9" r=".17"/>
<circle cx="199.4" cy="103.9" r=".17"/>
<circle cx="196.8" cy="106.4" r=".17"/>
<circle cx="199.4" cy="106.4" r=".17"/>
<circle cx="196.8" cy="109" r=".17"/>
<circle cx="199.4" cy="109" r=".17"/>
<circle cx="196.8" cy="111.5" r=".17"/>
<circle cx="199.4" cy="111.5" r=".17"/>
<circle cx="196.8" cy="114" r=".17"/>
<circle cx="199.4" cy="114" r=".17"/>
<circle cx="196.8" cy="116.6" r=".17"/>
<circle cx="199.4" cy="116.6" r=".17"/>
<circle cx="196.8" cy="119.1" r=".17"/>
<circle cx="199.4" cy="119.1" r=".17"/>
<circle cx="196.8" cy="121.7" r=".17"/>
<circle cx="199.4" cy="121.7" r=".17"/>
<circle cx="154.7" cy="73.4" r=".17"/>
<circle cx="157.2" cy="73.4" r=".17"/>
<circle cx="154.7" cy="75.9" r=".17"/>
<circle cx="157.2" cy="75.9" r=".17"/>
<circle cx="154.7" cy="78.5" r=".17"/>
<circle cx="157.2" cy="78.5" r=".17"/>
<circle cx="154.7" cy="81" r=".17"/>
<circle cx="157.2" cy="81" r=".17"/>
<circle cx="154.7" cy="83.6" r=".17"/>
<circle cx="157.2" cy="83.6" r=".17"/>
<circle cx="154.7" cy="86.1" r=".17"/>
<circle cx="157.2" cy="86.1" r=".17"/>
<circle cx="154.7" cy="88.6" r=".17"/>
<circle cx="157.2" cy="88.6" r=".17"/>
<circle cx="154.7" cy="91.2" r=".17"/>
<circle cx="157.2" cy="91.2" r=".17"/>
<circle cx="154.7" cy="93.7" r=".17"/>
<circle cx="157.2" cy="93.7" r=".17"/>
<circle cx="154.7" cy="96.3" r=".17"/>
<circle cx="157.2" cy="96.3" r=".17"/>
<circle cx="154.7" cy="98.8" r=".17"/>
<circle cx="157.2" cy="98.8" r=".17"/>
<circle cx="154.7" cy="101.3" r=".17"/>
<circle cx="157.2" cy="101.3" r=".17"/>
<circle cx="154.7" cy="103.9" r=".17"/>
<circle cx="157.2" cy="103.9" r=".17"/>
<circle cx="154.7" cy="106.4" r=".17"/>
<circle cx="157.2" cy="106.4" r=".17"/>
<circle cx="154.7" cy="109" r=".17"/>
<circle cx="157.2" cy="109" r=".17"/>
<circle cx="154.7" cy="111.5" r=".17"/>
<circle cx="157.2" cy="111.5" r=".17"/>
<circle cx="154.7" cy="114" r=".17"/>
<circle cx="157.2" cy="114" r=".17"/>
<circle cx="154.7" cy="116.6" r=".17"/>
<circle cx="157.2" cy="116.6" r=".17"/>
<circle cx="154.7" cy="119.1" r=".17"/>
<circle cx="157.2" cy="119.1" r=".17"/>
<circle cx="154.7" cy="121.7" r=".17"/>
<circle cx="157.2" cy="121.7" r=".17"/>
<circle cx="188.6" cy="73.4" r=".17"/>
<circle cx="191.1" cy="73.4" r=".17"/>
<circle cx="188.6" cy="75.9" r=".17"/>
<circle cx="191.1" cy="75.9" r=".17"/>
<circle cx="188.6" cy="78.5" r=".17"/>
<circle cx="191.1" cy="78.5" r=".17"/>
<circle cx="188.6" cy="81" r=".17"/>
<circle cx="191.1" cy="81" r=".17"/>
<circle cx="188.6" cy="83.6" r=".17"/>
<circle cx="191.1" cy="83.6" r=".17"/>
<circle cx="188.6" cy="86.1" r=".17"/>
<circle cx="191.1" cy="86.1" r=".17"/>
<circle cx="188.6" cy="88.6" r=".17"/>
<circle cx="191.1" cy="88.6" r=".17"/>
<circle cx="188.6" cy="91.2" r=".17"/>
<circle cx="191.1" cy="91.2" r=".17"/>
<circle cx="188.6" cy="93.7" r=".17"/>
<circle cx="191.1" cy="93.7" r=".17"/>
<circle cx="188.6" cy="96.3" r=".17"/>
<circle cx="191.1" cy="96.3" r=".17"/>
<circle cx="188.6" cy="98.8" r=".17"/>
<circle cx="191.1" cy="98.8" r=".17"/>
<circle cx="188.6" cy="101.3" r=".17"/>
<circle cx="191.1" cy="101.3" r=".17"/>
<circle cx="188.6" cy="103.9" r=".17"/>
<circle cx="191.1" cy="103.9" r=".17"/>
<circle cx="188.6" cy="106.4" r=".17"/>
<circle cx="191.1" cy="106.4" r=".17"/>
<circle cx="188.6" cy="109" r=".17"/>
<circle cx="191.1" cy="109" r=".17"/>
<circle cx="188.6" cy="111.5" r=".17"/>
<circle cx="191.1" cy="111.5" r=".17"/>
<circle cx="188.6" cy="114" r=".17"/>
<circle cx="191.1" cy="114" r=".17"/>
<circle cx="188.6" cy="116.6" r=".17"/>
<circle cx="191.1" cy="116.6" r=".17"/>
<circle cx="188.6" cy="119.1" r=".17"/>
<circle cx="191.1" cy="119.1" r=".17"/>
<circle cx="188.6" cy="121.7" r=".17"/>
<circle cx="191.1" cy="121.7" r=".17"/>
</g>
</svg>
